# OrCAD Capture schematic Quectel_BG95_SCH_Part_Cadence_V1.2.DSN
size A2

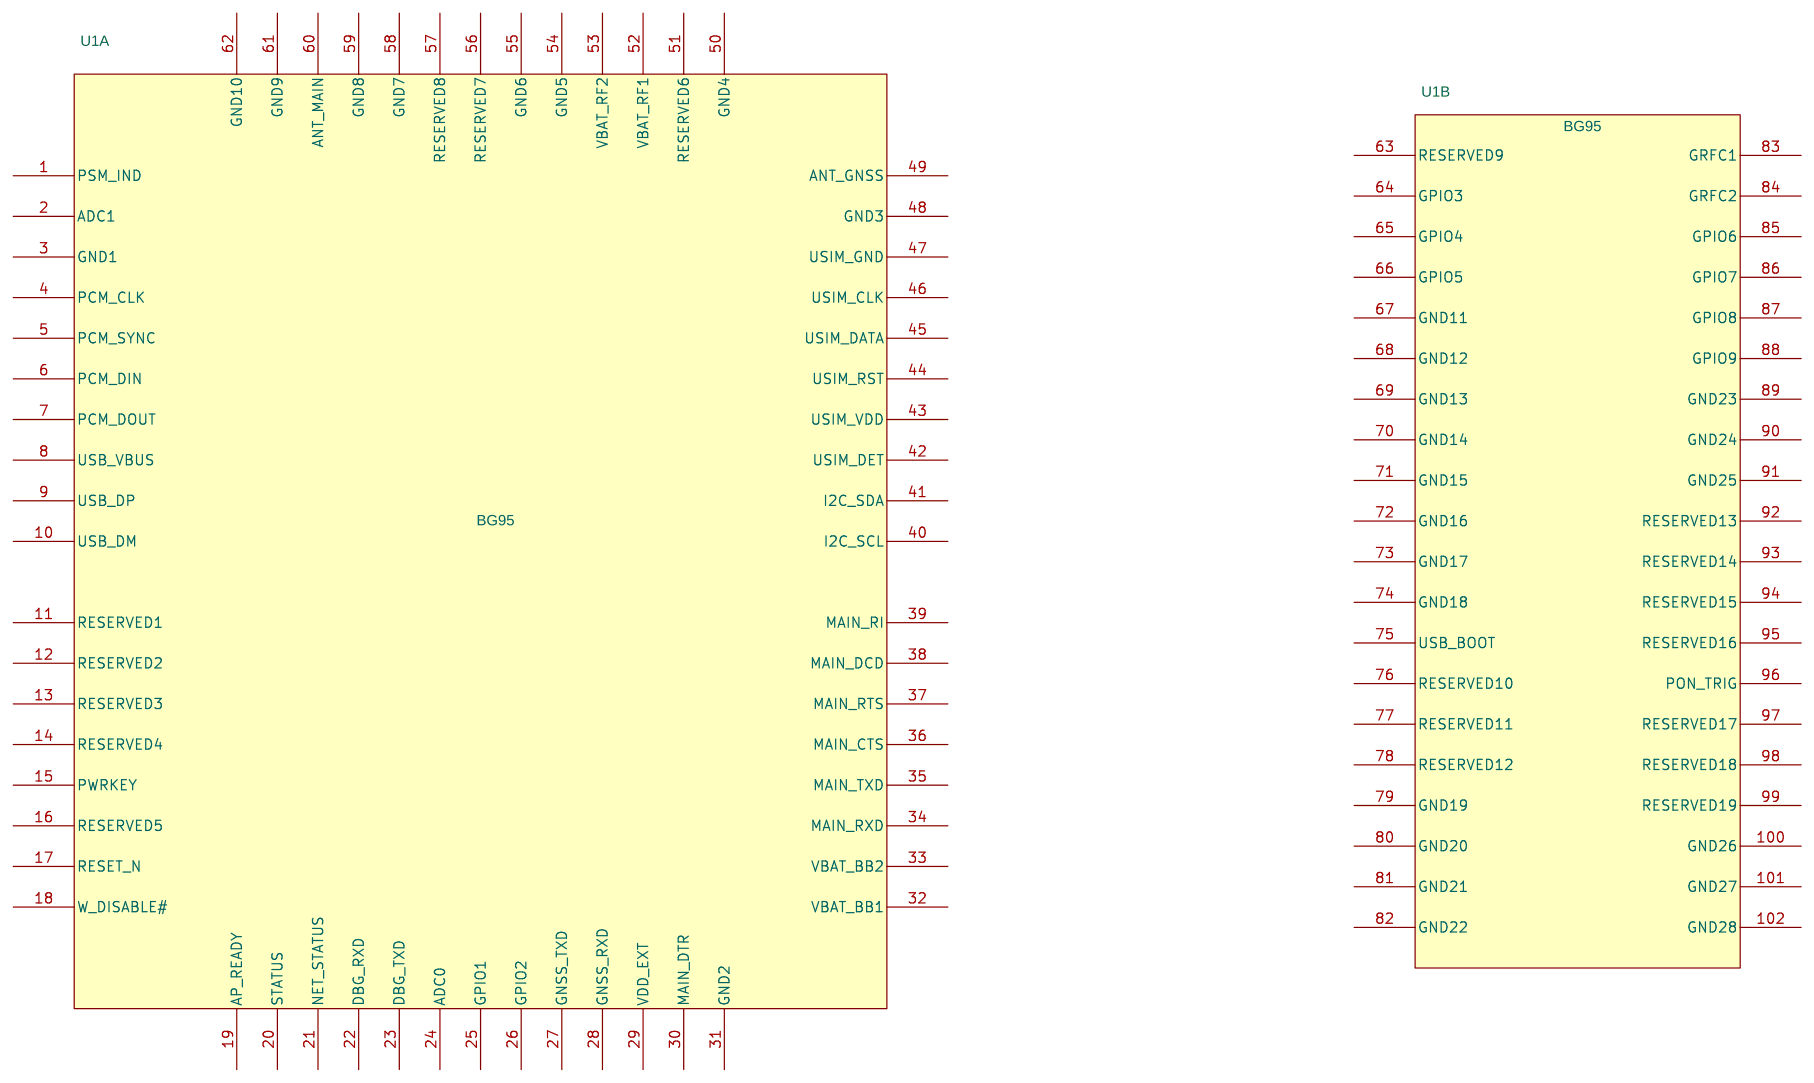
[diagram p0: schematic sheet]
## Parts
U1  BG95  [BG95]  (sections A,B)

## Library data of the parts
U1 = BG95_2

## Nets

Not connected (* = marked no-connect by the designer): U1 1(PSM_IND) 2(ADC1) 3(GND1) 4(PCM_CLK) 5(PCM_SYNC) 6(PCM_DIN) 7(PCM_DOUT) 8(USB_VBUS) 9(USB_DP) 10(USB_DM) 11(RESERVED1) 12(RESERVED2) 13(RESERVED3) 14(RESERVED4) 15(PWRKEY) 16(RESERVED5) 17(RESET_N) 18(W_DISABLE#) 19(AP_READY) 20(STATUS) 21(NET_STATUS) 22(DBG_RXD) 23(DBG_TXD) 24(ADC0) 25(GPIO1) 26(GPIO2) 27(GNSS_TXD) 28(GNSS_RXD) 29(VDD_EXT) 30(MAIN_DTR) 31(GND2) 32(VBAT_BB1) 33(VBAT_BB2) 34(MAIN_RXD) 35(MAIN_TXD) 36(MAIN_CTS) 37(MAIN_RTS) 38(MAIN_DCD) 39(MAIN_RI) 40(I2C_SCL) 41(I2C_SDA) 42(USIM_DET) 43(USIM_VDD) 44(USIM_RST) 45(USIM_DATA) 46(USIM_CLK) 47(USIM_GND) 48(GND3) 49(ANT_GNSS) 50(GND4) 51(RESERVED6) 52(VBAT_RF1) 53(VBAT_RF2) 54(GND5) 55(GND6) 56(RESERVED7) 57(RESERVED8) 58(GND7) 59(GND8) 60(ANT_MAIN) 61(GND9) 62(GND10) 63(RESERVED9) 64(GPIO3) 65(GPIO4) 66(GPIO5) 67(GND11) 68(GND12) 69(GND13) 70(GND14) 71(GND15) 72(GND16) 73(GND17) 74(GND18) 75(USB_BOOT) 76(RESERVED10) 77(RESERVED11) 78(RESERVED12) 79(GND19) 80(GND20) 81(GND21) 82(GND22) 83(GRFC1) 84(GRFC2) 85(GPIO6) 86(GPIO7) 87(GPIO8) 88(GPIO9) 89(GND23) 90(GND24) 91(GND25) 92(RESERVED13) 93(RESERVED14) 94(RESERVED15) 95(RESERVED16) 96(PON_TRIG) 97(RESERVED17) 98(RESERVED18) 99(RESERVED19) 100(GND26) 101(GND27) 102(GND28)
